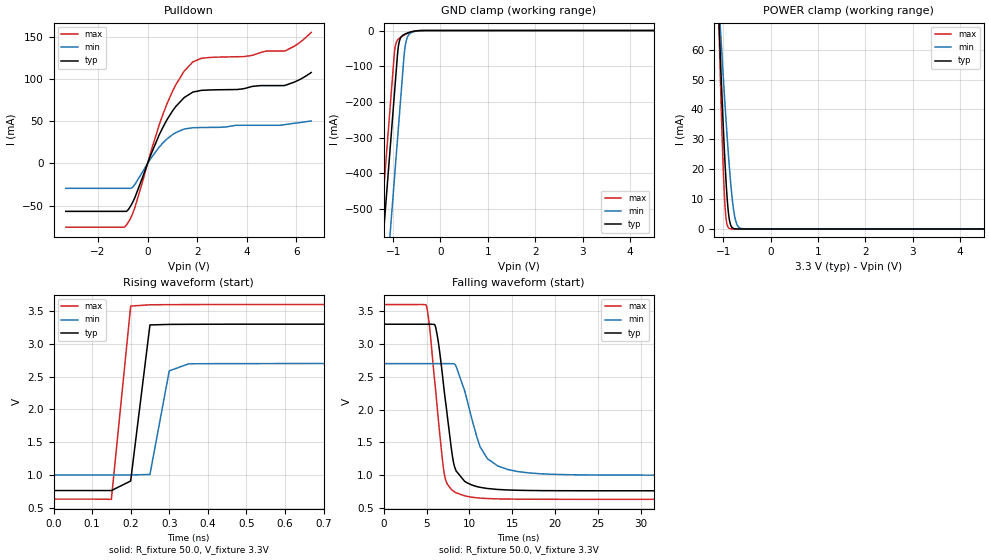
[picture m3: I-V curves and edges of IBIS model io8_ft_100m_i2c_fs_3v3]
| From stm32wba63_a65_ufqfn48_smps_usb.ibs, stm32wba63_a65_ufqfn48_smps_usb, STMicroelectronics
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[Model]   io8_ft_100m_i2c_fs_3v3
Model_type I/O_open_drain
Polarity   Non-Inverting
Enable   Active-Low
| CAP_THRESHOLD on pad IOFT is "UDTCAPC" :
| Rising=30.0% of vddiom   Falling=70.0% of vddiom
| C_comp min and max val. don't necessarily correlate with the min and max pvt
| but are the smallest and greatest pad capacitance found.
| var   typ   min   max
C_comp   3.81294pF  3.70667pF  3.87011pF
|C_comp_pulldown   3.81294pF  3.70667pF  3.87011pF
Vinl = 1.35V
Vinh = 1.8V
Vmeas = 1.65V   | Reference voltage for timing measurements
Cref  = 50.0pF   | Timing specification test load capacitance value
Rref  = 1.0MOhm   | Timing specification test load resistance value
Vref  = 1.815V   | Timing specification test load voltage
[Model Spec]
| TIME_THRESHOLD on pin ZII2CV11 is "CMOS" :
| Rising=50.0% of vdd   Falling=50.0% of vdd
Vinl 1.29050V 1.08050V 1.37650V
Vinh 1.79850V 1.52050V 1.90250V
| variable   typ   min   max
[Temperature Range] 25.0 140.0 -40.0
| variable   typ   min   max
[Voltage Range] 3.3V 2.7V 3.6V
| variable   typ   min   max
[POWER Clamp Reference] 3.3V 2.7V 3.6V
| variable   typ   min   max
[GND Clamp Reference] 0V 0V 0V
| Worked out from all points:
|   slope of the pulldown table from 0 to 0.495 V, typ, clamps not added: 14 ohm
|   GND clamp passes 1 mA (typ) near -0.51 V on its own axis
|   POWER clamp passes 1 mA (typ) near -0.83 V on its own axis
|   rising waveform, R_fixture 50.0, V_fixture 3.3V: 20-80 % time 32ps typ, 32.3ps min, 30.2ps max; typ from 0.764 V to 3.3 V
|   falling waveform, R_fixture 50.0, V_fixture 3.3V: 20-80 % time 1.43ns typ, 2.43ns min, 1.32ns max; typ from 3.3 V to 0.764 V
[POWER Clamp]
-3.3V     1.123A     753mA      1.645A
-1.09V    69.42mA    75.17mA    67.14mA
-1.08V    65.31mA    72.42mA    61.23mA
-1.06V    57.23mA    66.98mA    49.77mA
-1.01V    38.06mA    53.68mA    24.29mA
-970mV    24.36mA    43.46mA    9.575mA
-930mV    13.06mA    33.74mA    2.352mA
-870mV    3.065mA    20.56mA    165.9uA
-810mV    418.4uA    10.06mA    10.3uA
-760mV    69.41uA    4.321mA    1.009uA
-630mV    611.5nA    197uA      2.727nA
6.6V      0A         0A         0A
[GND Clamp]
-3.3V     -4.134A    -4.372A    -4.018A
-1.59V    -1.227A    -1.465A    -1.111A
-1.25V    -648.9mA   -886.9mA   -533mA
-980mV    -189.9mA   -427.9mA   -74mA
-960mV    -155.9mA   -393.9mA   -48.8mA
-910mV    -70.86mA   -308.9mA   -27.2mA
-880mV    -37.23mA   -257.9mA   -22.76mA
-770mV    -11.28mA   -71.59mA   -12.95mA
-730mV    -8.709mA   -32.74mA   -10.07mA
-630mV    -4.122mA   -6.943mA   -4.354mA
-370mV    -42.68uA   -212.2uA   -13.03uA
6.6V      2.311nA    506.4nA    1.057nA
| variable   typ   min   max
[Pullup Reference] 3.3V 2.7V 3.6V
| variable   typ   min   max
[Pulldown Reference] 0V 0V 0V
[Pulldown]
-3.3V     -56.7mA    -29.42mA   -75.36mA
-860mV    -56.67mA   -29.42mA   -72.94mA
-520mV    -40.69mA   -25.01mA   -52.64mA
460mV     33.25mA    19.09mA    44.92mA
800mV     52.54mA    29.36mA    71.75mA
1.14V     67.41mA    36.49mA    93.2mA
1.48V     77.97mA    40.67mA    109.3mA
1.83V     84.38mA    42.18mA    120.1mA
2.17V     86.37mA    42.45mA    124.3mA
3.88V     88.31mA    45.1mA     126.3mA
5.54V     92.28mA    45.89mA    133mA
6.6V      107.5mA    50.2mA     155mA
[Ramp]
dV/dt_r 1.52153V/251.09606ps 1.01893V/339.45043ps 1.77968V/235.86864ps
dV/dt_f 1.52157V/1.42762ns 1.019V/2.29966ns 1.77971V/1.31538ns
R_load = 50.0
| Removed startup time: 0s 0s 0s  .
| Removed end time: 900.0ps.
[Rising Waveform]
R_fixture   = 50.0
V_fixture   = 3.3V
V_fixture_min = 2.7V
V_fixture_max = 3.6V
0s        764mV      1.002V     633.8mV
150ps     764mV      1.002V     630.4mV
200ps     910.4mV    1.002V     3.576V
250ps     3.288V     1.009V     3.596V
300ps     3.297V     2.588V     3.598V
350ps     3.298V     2.695V     3.599V
900ps     3.3V       2.7V       3.6V
| Removed startup time: 0s 0s 0s  .
| Removed end time: 59.25ns.
[Falling Waveform]
R_fixture   = 50.0
V_fixture   = 3.3V
V_fixture_min = 2.7V
V_fixture_max = 3.6V
0s        3.3V       2.7V       3.6V
5ns       3.3V       2.7V       3.578V
5.4ns     3.301V     2.7V       3.207V
6.05ns    3.262V     2.7V       2.313V
7.05ns    2.303V     2.7V       1.044V
8ns       1.312V     2.699V     773.1mV
8.45ns    1.067V     2.66V      733.9mV
11.25ns   816.6mV    1.434V     652.7mV
14.5ns    776.1mV    1.087V     637.9mV
59.25ns   764mV      1.002V     633.8mV
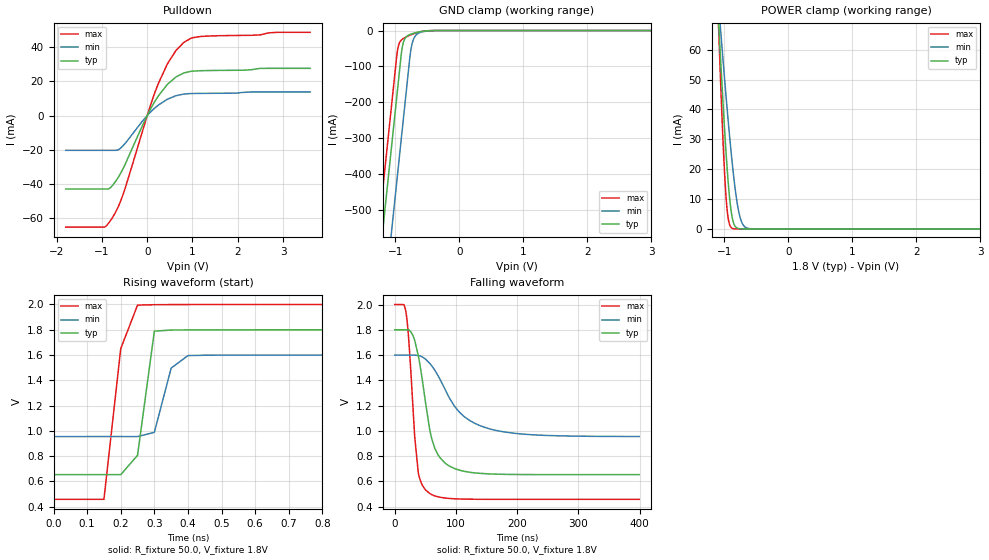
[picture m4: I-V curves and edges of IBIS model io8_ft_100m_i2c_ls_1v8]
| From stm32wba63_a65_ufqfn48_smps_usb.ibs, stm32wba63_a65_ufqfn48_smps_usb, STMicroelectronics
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[Model]   io8_ft_100m_i2c_ls_1v8
Model_type I/O_open_drain
Polarity   Non-Inverting
Enable   Active-Low
| CAP_THRESHOLD on pad IOFT is "UDTCAPC" :
| Rising=30.0% of vddiom   Falling=70.0% of vddiom
| C_comp min and max val. don't necessarily correlate with the min and max pvt
| but are the smallest and greatest pad capacitance found.
| var   typ   min   max
C_comp   3.34888pF  3.31958pF  3.48457pF
|C_comp_pulldown   3.34888pF  3.31958pF  3.48457pF
Vinl = 800.0mV
Vinh = 1.0V
Vmeas = 900.0mV   | Reference voltage for timing measurements
Cref  = 50.0pF   | Timing specification test load capacitance value
Rref  = 1.0MOhm   | Timing specification test load resistance value
Vref  = 990.0mV   | Timing specification test load voltage
[Model Spec]
| TIME_THRESHOLD on pin ZII2CV11 is "CMOS" :
| Rising=50.0% of vdd   Falling=50.0% of vdd
Vinl 702.50000mV 626.50000mV 788.50000mV
Vinh 1.09050V 959.50000mV 1.19650V
| variable   typ   min   max
[Temperature Range] 25.0 140.0 -40.0
| variable   typ   min   max
[Voltage Range] 1.8V 1.6V 2.0V
| variable   typ   min   max
[POWER Clamp Reference] 1.8V 1.6V 2.0V
| variable   typ   min   max
[GND Clamp Reference] 0V 0V 0V
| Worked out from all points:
|   slope of the pulldown table from 0 to 0.27 V, typ, clamps not added: 21.9 ohm
|   GND clamp passes 1 mA (typ) near -0.51 V on its own axis
|   POWER clamp passes 1 mA (typ) near -0.83 V on its own axis
|   rising waveform, R_fixture 50.0, V_fixture 1.8V: 20-80 % time 35ps typ, 38.1ps min, 43ps max; typ from 0.654 V to 1.8 V
|   falling waveform, R_fixture 50.0, V_fixture 1.8V: 20-80 % time 24.6ns typ, 55.3ns min, 13.1ns max; typ from 1.8 V to 0.654 V
[POWER Clamp]
-1.8V     396.4mA    285.5mA    556.9mA
-1.09V    69.42mA    75.17mA    67.14mA
-1.08V    65.31mA    72.42mA    61.23mA
-1.06V    57.23mA    66.98mA    49.77mA
-1.02V    41.75mA    56.3mA     28.91mA
-980mV    27.6mA     45.97mA    12.6mA
-940mV    15.59mA    36.11mA    3.485mA
-880mV    4.091mA    22.61mA    262.5uA
-820mV    594.6uA    11.56mA    16.39uA
-760mV    69.41uA    4.321mA    1.008uA
-630mV    611.2nA    197uA      2.486nA
3.6V      0A         0A         0A
[GND Clamp]
-1.8V     -1.583A    -1.82A     -1.468A
-1.43V    -953.9mA   -1.191A    -839.3mA
-1.24V    -630.9mA   -867.8mA   -516.3mA
-1.05V    -307.9mA   -544.8mA   -193.3mA
-980mV    -188.9mA   -425.8mA   -74.3mA
-950mV    -137.9mA   -374.8mA   -41.62mA
-890mV    -44.57mA   -272.8mA   -24.11mA
-800mV    -13.55mA   -119.8mA   -15.31mA
-760mV    -10.3mA    -56.67mA   -12.19mA
-720mV    -7.957mA   -26.08mA   -9.381mA
-540mV    -1.564mA   -2.435mA   -1.367mA
3.6V      1.281nA    268.1nA    531.2pA
| variable   typ   min   max
[Pullup Reference] 1.8V 1.6V 2.0V
| variable   typ   min   max
[Pulldown Reference] 0V 0V 0V
[Pulldown]
-1.8V     -42.97mA   -20.34mA   -65.35mA
-940mV    -42.97mA   -20.34mA   -65.31mA
-780mV    -41.3mA    -20.34mA   -60.25mA
-650mV    -36.58mA   -20.1mA    -53.93mA
-530mV    -30.86mA   -17.55mA   -45.89mA
0V        0A         -20fA      -3.2fA
250mV     11.67mA    6.208mA    19.03mA
460mV     18.64mA    9.755mA    30.89mA
630mV     22.5mA     11.58mA    37.88mA
810mV     24.97mA    12.61mA    42.87mA
1.18V     26.28mA    13mA       46.33mA
3.6V      27.68mA    13.83mA    48.76mA
[Ramp]
dV/dt_r 687.67238mV/314.31668ps 386.81556mV/611.51382ps 924.84926mV/229.78448ps
dV/dt_f 687.69262mV/24.38865ns 386.62487mV/55.14032ns 924.8647mV/12.22554ns
R_load = 50.0
| Removed startup time: 0s 0s 0s  .
| Removed end time: 1.75ns.
[Rising Waveform]
R_fixture   = 50.0
V_fixture   = 1.8V
V_fixture_min = 1.6V
V_fixture_max = 2.0V
0s        653.8mV    955.3mV    458.6mV
150ps     653.8mV    955.3mV    458.5mV
200ps     653.8mV    955.2mV    1.651V
250ps     806.7mV    955.1mV    1.995V
300ps     1.789V     988.6mV    1.998V
350ps     1.798V     1.497V     1.999V
400ps     1.799V     1.596V     2V
1.75ns    1.8V       1.6V       2V
| Removed startup time: 0s 0s 0s  .
| Removed end time: 399.25ns.
[Falling Waveform]
R_fixture   = 50.0
V_fixture   = 1.8V
V_fixture_min = 1.6V
V_fixture_max = 2.0V
0s        1.8V       1.6V       2V
17.9ns    1.8V       1.6V       1.95V
23.3ns    1.799V     1.6V       1.688V
32.6ns    1.716V     1.6V       951.4mV
38.45ns   1.595V     1.596V     666.8mV
57.05ns   1.011V     1.535V     504.9mV
81.5ns    748.1mV    1.335V     469.2mV
106ns     688.8mV    1.146V     461.2mV
146.7ns   661.7mV    1.028V     458.8mV
399.3ns   653.8mV    955.6mV    458.6mV
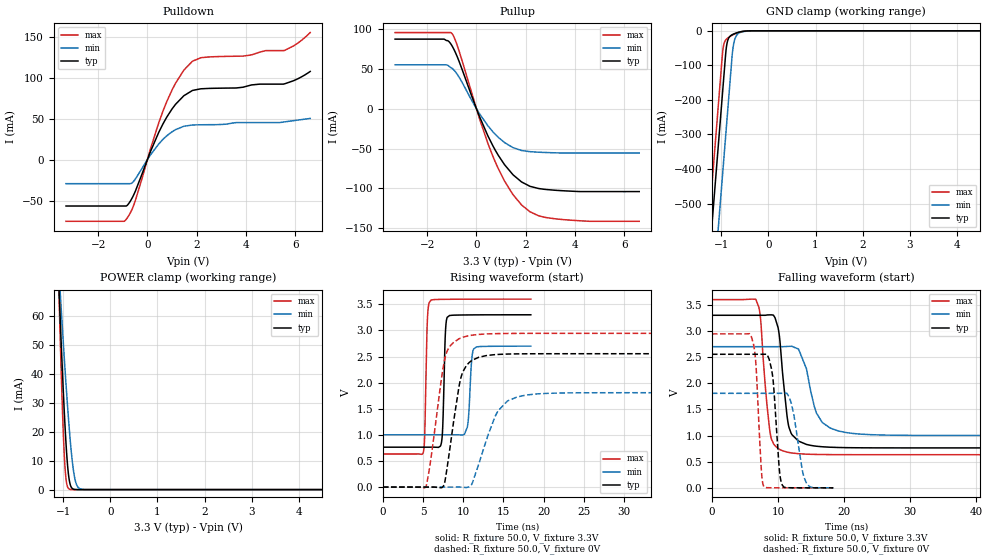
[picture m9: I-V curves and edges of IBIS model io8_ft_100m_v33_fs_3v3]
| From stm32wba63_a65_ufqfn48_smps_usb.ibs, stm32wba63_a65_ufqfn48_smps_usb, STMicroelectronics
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[Model]   io8_ft_100m_v33_fs_3v3
Model_type I/O
Polarity   Non-Inverting
Enable   Active-Low
| CAP_THRESHOLD on pad IOFT is "UDTCAPC" :
| Rising=30.0% of vddiom   Falling=70.0% of vddiom
| C_comp min and max val. don't necessarily correlate with the min and max pvt
| but are the smallest and greatest pad capacitance found.
| var   typ   min   max
C_comp   3.88674pF  3.77802pF  3.94187pF
|C_comp_pullup   2.41868pF  2.25967pF  2.53638pF
|C_comp_pulldown   1.46805pF  1.51834pF  1.40549pF
Vinl = 1.35V
Vinh = 1.8V
Vmeas = 1.65V   | Reference voltage for timing measurements
Cref  = 50.0pF   | Timing specification test load capacitance value
Rref  = 1.0MOhm   | Timing specification test load resistance value
Vref  = 1.815V   | Timing specification test load voltage
[Model Spec]
| TIME_THRESHOLD on pin ZIV33M is "CMOS" :
| Rising=50.0% of vddiom   Falling=50.0% of vddiom
Vinl 1.28450V 1.07450V 1.37050V
Vinh 1.79550V 1.51850V 1.89950V
| variable   typ   min   max
[Temperature Range] 25.0 140.0 -40.0
| variable   typ   min   max
[Voltage Range] 3.3V 2.7V 3.6V
| variable   typ   min   max
[POWER Clamp Reference] 3.3V 2.7V 3.6V
| variable   typ   min   max
[GND Clamp Reference] 0V 0V 0V
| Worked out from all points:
|   slope of the pulldown table from 0 to 0.495 V, typ, clamps not added: 14 ohm
|   slope of the pullup table from 0 to 0.495 V, typ, clamps not added: 13.8 ohm
|   GND clamp passes 1 mA (typ) near -0.51 V on its own axis
|   POWER clamp passes 1 mA (typ) near -0.83 V on its own axis
|   rising waveform, R_fixture 50.0, V_fixture 3.3V: 20-80 % time 262ps typ, 357ps min, 248ps max; typ from 0.764 V to 3.3 V
|   falling waveform, R_fixture 50.0, V_fixture 3.3V: 20-80 % time 1.18ns typ, 2.21ns min, 1.14ns max; typ from 3.3 V to 0.764 V
|   rising waveform, R_fixture 50.0, V_fixture 0V: 20-80 % time 1.5ns typ, 2.52ns min, 1.56ns max; typ from 0 V to 2.55 V
|   falling waveform, R_fixture 50.0, V_fixture 0V: 20-80 % time 833ps typ, 1.34ns min, 705ps max; typ from 2.55 V to 0 V
[POWER Clamp]
-3.3V     1.123A     753mA      1.645A
-1.09V    69.42mA    75.17mA    67.14mA
-1.08V    65.31mA    72.42mA    61.23mA
-1.06V    57.23mA    66.98mA    49.77mA
-1.01V    38.06mA    53.68mA    24.29mA
-970mV    24.36mA    43.46mA    9.575mA
-930mV    13.06mA    33.74mA    2.352mA
-870mV    3.065mA    20.56mA    165.9uA
-810mV    418.4uA    10.06mA    10.3uA
-760mV    69.41uA    4.321mA    1.009uA
-630mV    611.5nA    197uA      2.727nA
6.6V      0A         0A         0A
[GND Clamp]
-3.3V     -4.134A    -4.372A    -4.018A
-1.59V    -1.227A    -1.465A    -1.111A
-1.25V    -648.9mA   -886.9mA   -533mA
-980mV    -189.9mA   -427.9mA   -74mA
-960mV    -155.9mA   -393.9mA   -48.8mA
-910mV    -70.86mA   -308.9mA   -27.2mA
-880mV    -37.23mA   -257.9mA   -22.76mA
-770mV    -11.28mA   -71.59mA   -12.95mA
-730mV    -8.709mA   -32.74mA   -10.07mA
-630mV    -4.122mA   -6.943mA   -4.354mA
-370mV    -42.68uA   -212.2uA   -13.03uA
6.6V      2.31nA     506.4nA    1.057nA
| variable   typ   min   max
[Pullup Reference] 3.3V 2.7V 3.6V
| variable   typ   min   max
[Pulldown Reference] 0V 0V 0V
[Pullup]
-3.3V     87.39mA    55.15mA    95.62mA
-1.32V    87.39mA    55.15mA    95.62mA
-990mV    78.93mA    50.69mA    94.27mA
-710mV    59.9mA     39.94mA    72.94mA
120mV     -9.566mA   -6.09mA    -12.19mA
460mV     -33.83mA   -21.24mA   -43.26mA
800mV     -54.04mA   -33.36mA   -69.41mA
1.48V     -82.86mA   -48.82mA   -107.8mA
2.17V     -97.42mA   -53.93mA   -129.4mA
2.7V      -101mA     -54.85mA   -135.9mA
3.48V     -102.9mA   -55.62mA   -139.1mA
6.6V      -104.1mA   -55.62mA   -141.4mA
[Pulldown]
-3.3V     -56.7mA    -29.42mA   -75.36mA
-860mV    -56.67mA   -29.42mA   -72.94mA
-520mV    -40.69mA   -25.01mA   -52.64mA
460mV     33.25mA    19.09mA    44.92mA
800mV     52.54mA    29.36mA    71.75mA
1.14V     67.41mA    36.49mA    93.2mA
1.48V     77.97mA    40.67mA    109.3mA
1.83V     84.38mA    42.18mA    120.1mA
2.17V     86.37mA    42.45mA    124.3mA
3.88V     88.31mA    45.11mA    126.3mA
5.54V     92.28mA    45.89mA    133mA
6.6V      107.5mA    50.2mA     155mA
[Ramp]
dV/dt_r 1.53258V/1.50303ns 1.08444V/2.50691ns 1.76673V/1.55627ns
dV/dt_f 1.52157V/1.18011ns 1.019V/1.98919ns 1.77971V/1.13472ns
R_load = 50.0
| Removed startup time: 0s 0s 0s  .
| Removed end time: 18.4ns.
[Rising Waveform]
R_fixture   = 50.0
V_fixture   = 3.3V
V_fixture_min = 2.7V
V_fixture_max = 3.6V
0s        764mV      1.002V     633.8mV
5ns       764.1mV    1.002V     651.8mV
5.2ns     764.1mV    1.002V     962.5mV
5.55ns    764.1mV    1.002V     3.244V
6ns       764.1mV    1.002V     3.583V
7.35ns    920.2mV    1.002V     3.596V
8ns       3.251V     1.002V     3.597V
10.5ns    3.297V     1.145V     3.599V
11.3ns    3.298V     2.647V     3.599V
18.4ns    3.3V       2.699V     3.6V
| Removed startup time: 0s 0s 0s  .
| Removed end time: 58.4ns.
[Falling Waveform]
R_fixture   = 50.0
V_fixture   = 3.3V
V_fixture_min = 2.7V
V_fixture_max = 3.6V
0s        3.3V       2.7V       3.6V
6.65ns    3.3V       2.7V       3.602V
7.35ns    3.3V       2.7V       3.245V
8.85ns    3.308V     2.7V       1.02V
10ns      3.067V     2.7V       754.1mV
10.65ns   2.248V     2.7V       711.4mV
12.1ns    1.017V     2.706V     666.8mV
15.8ns    796.3mV    1.431V     639.2mV
19.1ns    772.2mV    1.088V     635.3mV
58.4ns    764mV      1.002V     633.8mV
| Removed startup time: 0s 0s 0s  .
| Removed end time: 58.35ns.
[Rising Waveform]
R_fixture   = 50.0
V_fixture   = 0V
V_fixture_min = 0V
V_fixture_max = 0V
0s        20.88nV    123.8nV    58.45nV
5.35ns    955.2nV    120.5nV    6.8mV
7.5ns     12.43mV    902.8nV    2.288V
8.25ns    645.9mV    7.199uV    2.677V
9.45ns    1.907V     132.3uV    2.838V
9.95ns    2.208V     -3.36mV    2.87V
11.1ns    2.428V     67.75mV    2.91V
14.3ns    2.541V     1.455V     2.94V
16.7ns    2.551V     1.727V     2.943V
58.35ns   2.554V     1.807V     2.945V
| Removed startup time: 0s 0s 0s  .
| Removed end time: 18.35ns.
[Falling Waveform]
R_fixture   = 50.0
V_fixture   = 0V
V_fixture_min = 0V
V_fixture_max = 0V
0s        2.554V     1.807V     2.945V
6ns       2.554V     1.807V     2.88V
6.6ns     2.554V     1.807V     2.453V
7.5ns     2.554V     1.807V     304.2mV
7.9ns     2.554V     1.807V     16.84mV
9.15ns    2.167V     1.807V     1.776mV
10.65ns   51.37mV    1.807V     999.5uV
12ns      2.153mV    1.622V     724.3uV
14.25ns   923.8uV    102mV      377uV
18.35ns   299.2uV    1.679mV    99.61uV
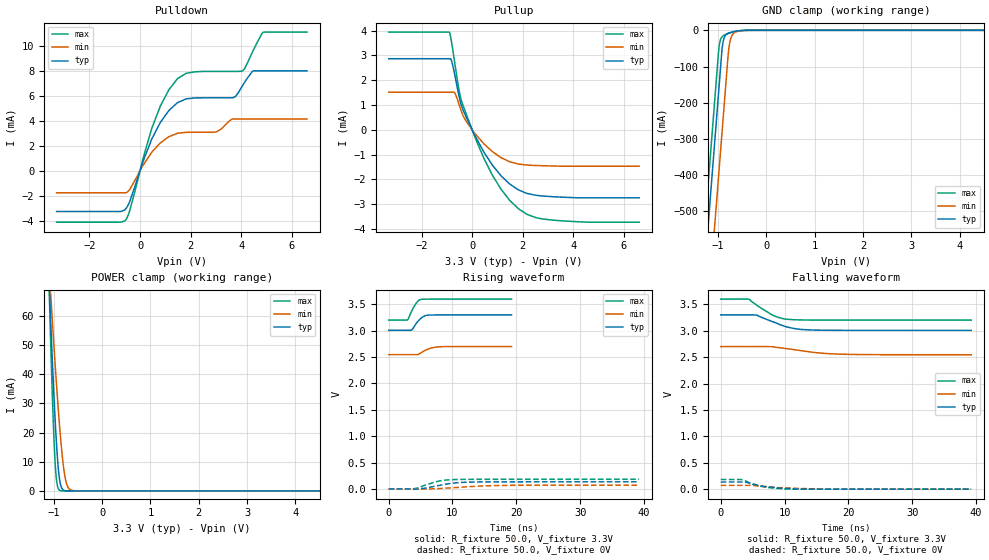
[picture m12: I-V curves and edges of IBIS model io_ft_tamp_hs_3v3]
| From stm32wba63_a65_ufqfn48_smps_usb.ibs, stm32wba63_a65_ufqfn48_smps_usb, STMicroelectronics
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[Model]   io_ft_tamp_hs_3v3
Model_type I/O
Polarity   Non-Inverting
Enable   Active-Low
| CAP_THRESHOLD on pad IOFT is "UDTCAPC" :
| Rising=30.0% of vddios   Falling=70.0% of vddios
| C_comp min and max val. don't necessarily correlate with the min and max pvt
| but are the smallest and greatest pad capacitance found.
| var   typ   min   max
C_comp   2.93630pF  2.87256pF  2.96827pF
|C_comp_pullup   1.79826pF  1.68491pF  1.83970pF
|C_comp_pulldown   1.13804pF  1.18765pF  1.12858pF
Vinl = 1.35V
Vinh = 1.8V
Vmeas = 1.65V   | Reference voltage for timing measurements
Cref  = 50.0pF   | Timing specification test load capacitance value
Rref  = 1.0MOhm   | Timing specification test load resistance value
Vref  = 1.815V   | Timing specification test load voltage
[Model Spec]
| TIME_THRESHOLD on pin ZIV11 is "CMOS" :
| Rising=50.0% of vdd   Falling=50.0% of vdd
Vinl 1.29050V 1.08050V 1.37650V
Vinh 1.79850V 1.52050V 1.90250V
| variable   typ   min   max
[Temperature Range] 25.0 140.0 -40.0
| variable   typ   min   max
[Voltage Range] 3.3V 2.7V 3.6V
| variable   typ   min   max
[POWER Clamp Reference] 3.3V 2.7V 3.6V
| variable   typ   min   max
[GND Clamp Reference] 0V 0V 0V
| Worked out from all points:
|   slope of the pulldown table from 0 to 0.495 V, typ, clamps not added: 186 ohm
|   slope of the pullup table from 0 to 0.495 V, typ, clamps not added: 523 ohm
|   GND clamp passes 1 mA (typ) near -0.54 V on its own axis
|   POWER clamp passes 1 mA (typ) near -0.83 V on its own axis
|   rising waveform, R_fixture 50.0, V_fixture 3.3V: 20-80 % time 1.19ns typ, 1.6ns min, 1.03ns max; typ from 3.01 V to 3.3 V
|   falling waveform, R_fixture 50.0, V_fixture 3.3V: 20-80 % time 3.95ns typ, 5.89ns min, 3.18ns max; typ from 3.3 V to 3.01 V
|   rising waveform, R_fixture 50.0, V_fixture 0V: 20-80 % time 3.71ns typ, 6.06ns min, 2.83ns max; typ from 0 V to 0.135 V
|   falling waveform, R_fixture 50.0, V_fixture 0V: 20-80 % time 3.87ns typ, 6.07ns min, 3.09ns max; typ from 0.135 V to 0 V
[POWER Clamp]
-3.3V     1.123A     753mA      1.645A
-1.09V    69.42mA    75.17mA    67.14mA
-1.08V    65.31mA    72.42mA    61.23mA
-1.06V    57.23mA    66.98mA    49.77mA
-1.01V    38.06mA    53.68mA    24.29mA
-970mV    24.36mA    43.46mA    9.575mA
-930mV    13.06mA    33.74mA    2.352mA
-870mV    3.065mA    20.56mA    165.9uA
-810mV    418.4uA    10.06mA    10.3uA
-760mV    69.41uA    4.321mA    1.008uA
-630mV    611nA      197uA      2.689nA
6.6V      0A         0A         0A
[GND Clamp]
-3.3V     -4.108A    -4.338A    -3.993A
-1.47V    -996.5mA   -1.227A    -882.1mA
-1.25V    -622.5mA   -853.4mA   -508.1mA
-990mV    -180.5mA   -411.4mA   -66.09mA
-980mV    -163.5mA   -394.4mA   -51.42mA
-900mV    -38.37mA   -258.4mA   -16.28mA
-860mV    -17.66mA   -190.4mA   -13.03mA
-780mV    -7.657mA   -58.45mA   -8.63mA
-740mV    -5.866mA   -26.35mA   -6.764mA
-690mV    -4.176mA   -10.78mA   -4.712mA
-450mV    -220.4uA   -529.3uA   -129.7uA
6.6V      1.984nA    498.7nA    735.2pA
| variable   typ   min   max
[Pullup Reference] 3.3V 2.7V 3.6V
| variable   typ   min   max
[Pulldown Reference] 0V 0V 0V
[Pullup]
-3.3V     2.869mA    1.518mA    3.942mA
-900mV    2.869mA    1.518mA    3.94mA
-820mV    2.799mA    1.518mA    3.578mA
-690mV    2.232mA    1.492mA    2.716mA
-460mV    1.115mA    847.8uA    1.317mA
-280mV    615.8uA    417.2uA    766uA
120mV     -251.9uA   -160.4uA   -321uA
800mV     -1.423mA   -878.8uA   -1.828mA
1.14V     -1.853mA   -1.12mA    -2.394mA
1.83V     -2.424mA   -1.383mA   -3.184mA
2.85V     -2.675mA   -1.45mA    -3.605mA
6.6V      -2.743mA   -1.466mA   -3.726mA
[Pulldown]
-3.3V     -3.274mA   -1.782mA   -4.133mA
-570mV    -3.064mA   -1.782mA   -3.957mA
-410mV    -2.48mA    -1.511mA   -3.207mA
460mV     2.522mA    1.473mA    3.369mA
800mV     3.858mA    2.222mA    5.168mA
1.48V     5.45mA     2.995mA    7.37mA
3.01V     5.836mA    3.097mA    7.954mA
3.67V     5.848mA    4.142mA    7.954mA
4.04V     6.772mA    4.142mA    7.991mA
4.45V     7.963mA    4.142mA    9.539mA
4.88V     8.002mA    4.142mA    11.1mA
6.6V      8.002mA    4.142mA    11.1mA
[Ramp]
dV/dt_r 80.90324mV/3.7007ns 43.28968mV/6.04832ns 109.86673mV/2.82874ns
dV/dt_f 175.10507mV/3.92924ns 92.30106mV/5.86434ns 238.66588mV/3.18516ns
R_load = 50.0
| Removed startup time: 0s 0s 0s  .
| Removed end time: 19.25ns.
[Rising Waveform]
R_fixture   = 50.0
V_fixture   = 3.3V
V_fixture_min = 2.7V
V_fixture_max = 3.6V
0s        3.008V     2.546V     3.202V
2.95ns    3.008V     2.546V     3.205V
3.15ns    3.008V     2.546V     3.243V
3.6ns     3.013V     2.546V     3.368V
4.25ns    3.125V     2.546V     3.508V
4.7ns     3.192V     2.555V     3.572V
5.1ns     3.239V     2.583V     3.593V
5.95ns    3.292V     2.64V      3.598V
7.9ns     3.299V     2.695V     3.599V
19.25ns   3.3V       2.7V       3.6V
| Removed startup time: 0s 0s 0s  .
| Removed end time: 39.25ns.
[Falling Waveform]
R_fixture   = 50.0
V_fixture   = 3.3V
V_fixture_min = 2.7V
V_fixture_max = 3.6V
0s        3.3V       2.7V       3.6V
4.45ns    3.301V     2.7V       3.597V
5.65ns    3.297V     2.7V       3.484V
8ns       3.179V     2.699V     3.306V
9.45ns    3.109V     2.676V     3.24V
10.45ns   3.071V     2.66V      3.218V
12.85ns   3.024V     2.619V     3.205V
15.25ns   3.012V     2.582V     3.203V
18.45ns   3.009V     2.558V     3.202V
39.25ns   3.008V     2.546V     3.202V
| Removed startup time: 0s 0s 0s  .
| Removed end time: 39.25ns.
[Rising Waveform]
R_fixture   = 50.0
V_fixture   = 0V
V_fixture_min = 0V
V_fixture_max = 0V
0s        79.54nV    353.3nV    261.5nV
3.7ns     -2.245mV   24.78uV    -1.434mV
4.55ns    -1.646mV   -799.7uV   20.77mV
5.4ns     10.46mV    -1.763mV   57.7mV
7.8ns     64.19mV    7.099mV    147.4mV
8.8ns     87.4mV     14mV       166.7mV
10.1ns    111mV      23.43mV    177.4mV
12.85ns   130.1mV    45.23mV    182.5mV
18.45ns   134.7mV    67.83mV    183.1mV
39.25ns   134.8mV    72.15mV    183.1mV
| Removed startup time: 0s 0s 0s  .
| Removed end time: 39.25ns.
[Falling Waveform]
R_fixture   = 50.0
V_fixture   = 0V
V_fixture_min = 0V
V_fixture_max = 0V
0s        134.9mV    72.18mV    183.1mV
3.2ns     134.8mV    72.18mV    181.9mV
3.95ns    130.6mV    72.15mV    152.5mV
4.95ns    102.6mV    69.89mV    92.98mV
6ns       68.52mV    59.16mV    60.61mV
8ns       34.51mV    38.5mV     23.31mV
10.2ns    13.22mV    23.39mV    2.232mV
12.85ns   817.1uV    12.04mV    226.7uV
17.65ns   89.51uV    988.5uV    24.17uV
39.25ns   157.3nV    3.032uV    275.3nV
